VERSION 5.7 ;
  NOWIREEXTENSIONATPIN ON ;
  DIVIDERCHAR "/" ;
  BUSBITCHARS "[]" ;
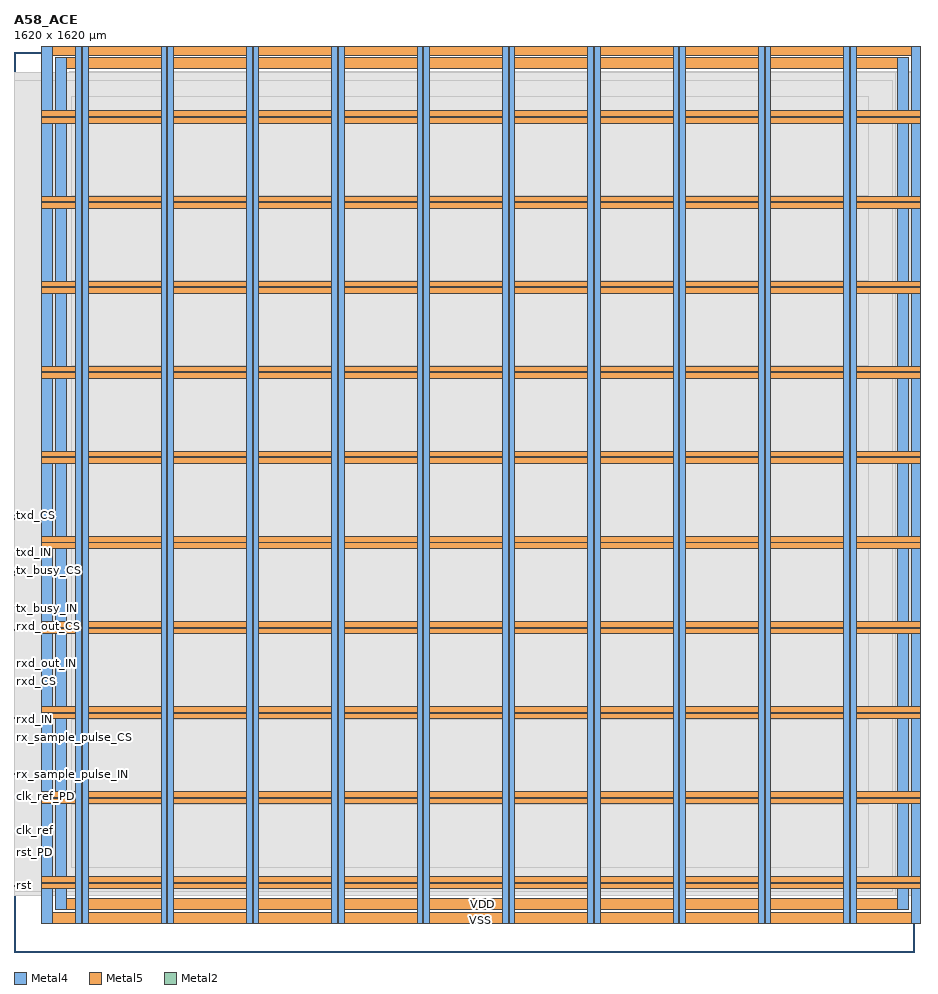
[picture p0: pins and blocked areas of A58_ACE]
MACRO A58_ACE
  CLASS BLOCK ;
  FOREIGN A58_ACE ;
  ORIGIN 0.000 0.000 ;
  SIZE 1620.000 BY 1620.000 ;
  PIN VDD
    DIRECTION INOUT ;
    USE POWER ;
    PORT
      LAYER Metal4 ;
        RECT 74.240 75.920 94.240 1609.680 ;
    END
    PORT
      LAYER Metal4 ;
        RECT 1590.800 75.920 1610.800 1609.680 ;
    END
    PORT
      LAYER Metal5 ;
        RECT 74.240 75.920 1610.800 95.920 ;
    END
    PORT
      LAYER Metal5 ;
        RECT 74.240 1589.680 1610.800 1609.680 ;
    END
    PORT
      LAYER Metal4 ;
        RECT 111.560 51.120 121.560 1634.480 ;
    END
    PORT
      LAYER Metal4 ;
        RECT 265.160 51.120 275.160 1634.480 ;
    END
    PORT
      LAYER Metal4 ;
        RECT 418.760 51.120 428.760 1634.480 ;
    END
    PORT
      LAYER Metal4 ;
        RECT 572.360 51.120 582.360 1634.480 ;
    END
    PORT
      LAYER Metal4 ;
        RECT 725.960 51.120 735.960 1634.480 ;
    END
    PORT
      LAYER Metal4 ;
        RECT 879.560 51.120 889.560 1634.480 ;
    END
    PORT
      LAYER Metal4 ;
        RECT 1033.160 51.120 1043.160 1634.480 ;
    END
    PORT
      LAYER Metal4 ;
        RECT 1186.760 51.120 1196.760 1634.480 ;
    END
    PORT
      LAYER Metal4 ;
        RECT 1340.360 51.120 1350.360 1634.480 ;
    END
    PORT
      LAYER Metal4 ;
        RECT 1493.960 51.120 1503.960 1634.480 ;
    END
    PORT
      LAYER Metal5 ;
        RECT 49.440 113.570 1635.600 123.570 ;
    END
    PORT
      LAYER Metal5 ;
        RECT 49.440 266.750 1635.600 276.750 ;
    END
    PORT
      LAYER Metal5 ;
        RECT 49.440 419.930 1635.600 429.930 ;
    END
    PORT
      LAYER Metal5 ;
        RECT 49.440 573.110 1635.600 583.110 ;
    END
    PORT
      LAYER Metal5 ;
        RECT 49.440 726.290 1635.600 736.290 ;
    END
    PORT
      LAYER Metal5 ;
        RECT 49.440 879.470 1635.600 889.470 ;
    END
    PORT
      LAYER Metal5 ;
        RECT 49.440 1032.650 1635.600 1042.650 ;
    END
    PORT
      LAYER Metal5 ;
        RECT 49.440 1185.830 1635.600 1195.830 ;
    END
    PORT
      LAYER Metal5 ;
        RECT 49.440 1339.010 1635.600 1349.010 ;
    END
    PORT
      LAYER Metal5 ;
        RECT 49.440 1492.190 1635.600 1502.190 ;
    END
  END VDD
  PIN VSS
    DIRECTION INOUT ;
    USE GROUND ;
    PORT
      LAYER Metal4 ;
        RECT 49.440 51.120 69.440 1634.480 ;
    END
    PORT
      LAYER Metal4 ;
        RECT 1615.600 51.120 1635.600 1634.480 ;
    END
    PORT
      LAYER Metal5 ;
        RECT 49.440 51.120 1635.600 71.120 ;
    END
    PORT
      LAYER Metal5 ;
        RECT 49.440 1614.480 1635.600 1634.480 ;
    END
    PORT
      LAYER Metal4 ;
        RECT 123.260 51.120 133.260 1634.480 ;
    END
    PORT
      LAYER Metal4 ;
        RECT 276.860 51.120 286.860 1634.480 ;
    END
    PORT
      LAYER Metal4 ;
        RECT 430.460 51.120 440.460 1634.480 ;
    END
    PORT
      LAYER Metal4 ;
        RECT 584.060 51.120 594.060 1634.480 ;
    END
    PORT
      LAYER Metal4 ;
        RECT 737.660 51.120 747.660 1634.480 ;
    END
    PORT
      LAYER Metal4 ;
        RECT 891.260 51.120 901.260 1634.480 ;
    END
    PORT
      LAYER Metal4 ;
        RECT 1044.860 51.120 1054.860 1634.480 ;
    END
    PORT
      LAYER Metal4 ;
        RECT 1198.460 51.120 1208.460 1634.480 ;
    END
    PORT
      LAYER Metal4 ;
        RECT 1352.060 51.120 1362.060 1634.480 ;
    END
    PORT
      LAYER Metal4 ;
        RECT 1505.660 51.120 1515.660 1634.480 ;
    END
    PORT
      LAYER Metal5 ;
        RECT 49.440 125.270 1635.600 135.270 ;
    END
    PORT
      LAYER Metal5 ;
        RECT 49.440 278.450 1635.600 288.450 ;
    END
    PORT
      LAYER Metal5 ;
        RECT 49.440 431.630 1635.600 441.630 ;
    END
    PORT
      LAYER Metal5 ;
        RECT 49.440 584.810 1635.600 594.810 ;
    END
    PORT
      LAYER Metal5 ;
        RECT 49.440 737.990 1635.600 747.990 ;
    END
    PORT
      LAYER Metal5 ;
        RECT 49.440 891.170 1635.600 901.170 ;
    END
    PORT
      LAYER Metal5 ;
        RECT 49.440 1044.350 1635.600 1054.350 ;
    END
    PORT
      LAYER Metal5 ;
        RECT 49.440 1197.530 1635.600 1207.530 ;
    END
    PORT
      LAYER Metal5 ;
        RECT 49.440 1350.710 1635.600 1360.710 ;
    END
    PORT
      LAYER Metal5 ;
        RECT 49.440 1503.890 1635.600 1513.890 ;
    END
  END VSS
  PIN clk_ref
    DIRECTION INPUT ;
    USE SIGNAL ;
    ANTENNAGATEAREA 14.368000 ;
    PORT
      LAYER Metal2 ;
        RECT 0.000 218.760 1.000 219.140 ;
    END
  END clk_ref
  PIN clk_ref_PD
    DIRECTION OUTPUT ;
    USE SIGNAL ;
    ANTENNADIFFAREA 0.360800 ;
    PORT
      LAYER Metal2 ;
        RECT 0.000 279.290 1.000 279.670 ;
    END
  END clk_ref_PD
  PIN clk_ref_PU
    DIRECTION OUTPUT ;
    USE SIGNAL ;
    ANTENNADIFFAREA 0.360800 ;
    PORT
      LAYER Metal2 ;
        RECT 0.000 283.655 1.000 284.035 ;
    END
  END clk_ref_PU
  PIN rst
    DIRECTION INPUT ;
    USE SIGNAL ;
    ANTENNAGATEAREA 4.408000 ;
    PORT
      LAYER Metal2 ;
        RECT 0.000 118.760 1.000 119.140 ;
    END
  END rst
  PIN rst_PD
    DIRECTION OUTPUT ;
    USE SIGNAL ;
    ANTENNADIFFAREA 0.360800 ;
    PORT
      LAYER Metal2 ;
        RECT 0.000 179.290 1.000 179.670 ;
    END
  END rst_PD
  PIN rst_PU
    DIRECTION OUTPUT ;
    USE SIGNAL ;
    ANTENNADIFFAREA 0.360800 ;
    PORT
      LAYER Metal2 ;
        RECT 0.000 183.655 1.000 184.035 ;
    END
  END rst_PU
  PIN rx_sample_pulse_CS
    DIRECTION OUTPUT ;
    USE SIGNAL ;
    ANTENNADIFFAREA 0.360800 ;
    PORT
      LAYER Metal2 ;
        RECT 0.000 386.260 1.000 386.640 ;
    END
  END rx_sample_pulse_CS
  PIN rx_sample_pulse_IE
    DIRECTION OUTPUT ;
    USE SIGNAL ;
    ANTENNADIFFAREA 0.360800 ;
    PORT
      LAYER Metal2 ;
        RECT 0.000 378.235 1.000 378.615 ;
    END
  END rx_sample_pulse_IE
  PIN rx_sample_pulse_IN
    DIRECTION INPUT ;
    USE SIGNAL ;
    PORT
      LAYER Metal2 ;
        RECT 0.000 318.760 1.000 319.140 ;
    END
  END rx_sample_pulse_IN
  PIN rx_sample_pulse_OE
    DIRECTION OUTPUT ;
    USE SIGNAL ;
    ANTENNADIFFAREA 0.536800 ;
    PORT
      LAYER Metal2 ;
        RECT 0.000 319.490 1.000 319.870 ;
    END
  END rx_sample_pulse_OE
  PIN rx_sample_pulse_OUT
    DIRECTION OUTPUT ;
    USE SIGNAL ;
    ANTENNADIFFAREA 1.986000 ;
    PORT
      LAYER Metal2 ;
        RECT 0.000 320.220 1.000 320.600 ;
    END
  END rx_sample_pulse_OUT
  PIN rx_sample_pulse_PD
    DIRECTION OUTPUT ;
    USE SIGNAL ;
    ANTENNADIFFAREA 0.360800 ;
    PORT
      LAYER Metal2 ;
        RECT 0.000 379.290 1.000 379.670 ;
    END
  END rx_sample_pulse_PD
  PIN rx_sample_pulse_PU
    DIRECTION OUTPUT ;
    USE SIGNAL ;
    ANTENNADIFFAREA 0.360800 ;
    PORT
      LAYER Metal2 ;
        RECT 0.000 383.655 1.000 384.035 ;
    END
  END rx_sample_pulse_PU
  PIN rx_sample_pulse_SL
    DIRECTION OUTPUT ;
    USE SIGNAL ;
    ANTENNADIFFAREA 0.360800 ;
    PORT
      LAYER Metal2 ;
        RECT 0.000 320.950 1.000 321.330 ;
    END
  END rx_sample_pulse_SL
  PIN rxd_CS
    DIRECTION OUTPUT ;
    USE SIGNAL ;
    ANTENNADIFFAREA 0.536800 ;
    PORT
      LAYER Metal2 ;
        RECT 0.000 486.260 1.000 486.640 ;
    END
  END rxd_CS
  PIN rxd_IE
    DIRECTION OUTPUT ;
    USE SIGNAL ;
    ANTENNADIFFAREA 0.536800 ;
    PORT
      LAYER Metal2 ;
        RECT 0.000 478.235 1.000 478.615 ;
    END
  END rxd_IE
  PIN rxd_IN
    DIRECTION INPUT ;
    USE SIGNAL ;
    ANTENNAGATEAREA 0.396000 ;
    PORT
      LAYER Metal2 ;
        RECT 0.000 418.760 1.000 419.140 ;
    END
  END rxd_IN
  PIN rxd_OE
    DIRECTION OUTPUT ;
    USE SIGNAL ;
    ANTENNADIFFAREA 0.360800 ;
    PORT
      LAYER Metal2 ;
        RECT 0.000 419.490 1.000 419.870 ;
    END
  END rxd_OE
  PIN rxd_PD
    DIRECTION OUTPUT ;
    USE SIGNAL ;
    ANTENNADIFFAREA 0.360800 ;
    PORT
      LAYER Metal2 ;
        RECT 0.000 479.290 1.000 479.670 ;
    END
  END rxd_PD
  PIN rxd_PU
    DIRECTION OUTPUT ;
    USE SIGNAL ;
    ANTENNADIFFAREA 0.360800 ;
    PORT
      LAYER Metal2 ;
        RECT 0.000 483.655 1.000 484.035 ;
    END
  END rxd_PU
  PIN rxd_SL
    DIRECTION OUTPUT ;
    USE SIGNAL ;
    ANTENNADIFFAREA 0.536800 ;
    PORT
      LAYER Metal2 ;
        RECT 0.000 420.950 1.000 421.330 ;
    END
  END rxd_SL
  PIN rxd_out
    DIRECTION OUTPUT ;
    USE SIGNAL ;
    ANTENNADIFFAREA 0.360800 ;
    PORT
      LAYER Metal2 ;
        RECT 0.000 420.220 1.000 420.600 ;
    END
  END rxd_out
  PIN rxd_out_CS
    DIRECTION OUTPUT ;
    USE SIGNAL ;
    ANTENNADIFFAREA 0.360800 ;
    PORT
      LAYER Metal2 ;
        RECT 0.000 586.260 1.000 586.640 ;
    END
  END rxd_out_CS
  PIN rxd_out_IE
    DIRECTION OUTPUT ;
    USE SIGNAL ;
    ANTENNADIFFAREA 0.360800 ;
    PORT
      LAYER Metal2 ;
        RECT 0.000 578.235 1.000 578.615 ;
    END
  END rxd_out_IE
  PIN rxd_out_IN
    DIRECTION INPUT ;
    USE SIGNAL ;
    PORT
      LAYER Metal2 ;
        RECT 0.000 518.760 1.000 519.140 ;
    END
  END rxd_out_IN
  PIN rxd_out_OE
    DIRECTION OUTPUT ;
    USE SIGNAL ;
    ANTENNADIFFAREA 0.536800 ;
    PORT
      LAYER Metal2 ;
        RECT 0.000 519.490 1.000 519.870 ;
    END
  END rxd_out_OE
  PIN rxd_out_OUT
    DIRECTION OUTPUT ;
    USE SIGNAL ;
    ANTENNADIFFAREA 1.986000 ;
    PORT
      LAYER Metal2 ;
        RECT 0.000 520.220 1.000 520.600 ;
    END
  END rxd_out_OUT
  PIN rxd_out_PD
    DIRECTION OUTPUT ;
    USE SIGNAL ;
    ANTENNADIFFAREA 0.360800 ;
    PORT
      LAYER Metal2 ;
        RECT 0.000 579.290 1.000 579.670 ;
    END
  END rxd_out_PD
  PIN rxd_out_PU
    DIRECTION OUTPUT ;
    USE SIGNAL ;
    ANTENNADIFFAREA 0.360800 ;
    PORT
      LAYER Metal2 ;
        RECT 0.000 583.655 1.000 584.035 ;
    END
  END rxd_out_PU
  PIN rxd_out_SL
    DIRECTION OUTPUT ;
    USE SIGNAL ;
    ANTENNADIFFAREA 0.360800 ;
    PORT
      LAYER Metal2 ;
        RECT 0.000 520.950 1.000 521.330 ;
    END
  END rxd_out_SL
  PIN tx_busy_CS
    DIRECTION OUTPUT ;
    USE SIGNAL ;
    ANTENNADIFFAREA 0.360800 ;
    PORT
      LAYER Metal2 ;
        RECT 0.000 686.260 1.000 686.640 ;
    END
  END tx_busy_CS
  PIN tx_busy_IE
    DIRECTION OUTPUT ;
    USE SIGNAL ;
    ANTENNADIFFAREA 0.360800 ;
    PORT
      LAYER Metal2 ;
        RECT 0.000 678.235 1.000 678.615 ;
    END
  END tx_busy_IE
  PIN tx_busy_IN
    DIRECTION INPUT ;
    USE SIGNAL ;
    PORT
      LAYER Metal2 ;
        RECT 0.000 618.760 1.000 619.140 ;
    END
  END tx_busy_IN
  PIN tx_busy_OE
    DIRECTION OUTPUT ;
    USE SIGNAL ;
    ANTENNADIFFAREA 0.536800 ;
    PORT
      LAYER Metal2 ;
        RECT 0.000 619.490 1.000 619.870 ;
    END
  END tx_busy_OE
  PIN tx_busy_OUT
    DIRECTION OUTPUT ;
    USE SIGNAL ;
    ANTENNADIFFAREA 1.986000 ;
    PORT
      LAYER Metal2 ;
        RECT 0.000 620.220 1.000 620.600 ;
    END
  END tx_busy_OUT
  PIN tx_busy_PD
    DIRECTION OUTPUT ;
    USE SIGNAL ;
    ANTENNADIFFAREA 0.360800 ;
    PORT
      LAYER Metal2 ;
        RECT 0.000 679.290 1.000 679.670 ;
    END
  END tx_busy_PD
  PIN tx_busy_PU
    DIRECTION OUTPUT ;
    USE SIGNAL ;
    ANTENNADIFFAREA 0.360800 ;
    PORT
      LAYER Metal2 ;
        RECT 0.000 683.655 1.000 684.035 ;
    END
  END tx_busy_PU
  PIN tx_busy_SL
    DIRECTION OUTPUT ;
    USE SIGNAL ;
    ANTENNADIFFAREA 0.360800 ;
    PORT
      LAYER Metal2 ;
        RECT 0.000 620.950 1.000 621.330 ;
    END
  END tx_busy_SL
  PIN txd_CS
    DIRECTION OUTPUT ;
    USE SIGNAL ;
    ANTENNADIFFAREA 0.360800 ;
    PORT
      LAYER Metal2 ;
        RECT 0.000 786.260 1.000 786.640 ;
    END
  END txd_CS
  PIN txd_IE
    DIRECTION OUTPUT ;
    USE SIGNAL ;
    ANTENNADIFFAREA 0.360800 ;
    PORT
      LAYER Metal2 ;
        RECT 0.000 778.235 1.000 778.615 ;
    END
  END txd_IE
  PIN txd_IN
    DIRECTION INPUT ;
    USE SIGNAL ;
    PORT
      LAYER Metal2 ;
        RECT 0.000 718.760 1.000 719.140 ;
    END
  END txd_IN
  PIN txd_OE
    DIRECTION OUTPUT ;
    USE SIGNAL ;
    ANTENNADIFFAREA 0.536800 ;
    PORT
      LAYER Metal2 ;
        RECT 0.000 719.490 1.000 719.870 ;
    END
  END txd_OE
  PIN txd_OUT
    DIRECTION OUTPUT ;
    USE SIGNAL ;
    ANTENNADIFFAREA 1.986000 ;
    PORT
      LAYER Metal2 ;
        RECT 0.000 720.220 1.000 720.600 ;
    END
  END txd_OUT
  PIN txd_PD
    DIRECTION OUTPUT ;
    USE SIGNAL ;
    ANTENNADIFFAREA 0.360800 ;
    PORT
      LAYER Metal2 ;
        RECT 0.000 779.290 1.000 779.670 ;
    END
  END txd_PD
  PIN txd_PU
    DIRECTION OUTPUT ;
    USE SIGNAL ;
    ANTENNADIFFAREA 0.360800 ;
    PORT
      LAYER Metal2 ;
        RECT 0.000 783.655 1.000 784.035 ;
    END
  END txd_PU
  PIN txd_SL
    DIRECTION OUTPUT ;
    USE SIGNAL ;
    ANTENNADIFFAREA 0.360800 ;
    PORT
      LAYER Metal2 ;
        RECT 0.000 720.950 1.000 721.330 ;
    END
  END txd_SL
  OBS
      LAYER Nwell ;
        RECT 99.810 101.490 1615.470 1584.110 ;
      LAYER Metal1 ;
        RECT 100.240 101.620 1615.040 1583.980 ;
      LAYER Metal2 ;
        RECT 0.140 786.940 1585.780 1583.870 ;
        RECT 1.300 785.960 1585.780 786.940 ;
        RECT 0.140 784.335 1585.780 785.960 ;
        RECT 1.300 783.355 1585.780 784.335 ;
        RECT 0.140 779.970 1585.780 783.355 ;
        RECT 1.300 778.990 1585.780 779.970 ;
        RECT 0.140 778.915 1585.780 778.990 ;
        RECT 1.300 777.935 1585.780 778.915 ;
        RECT 0.140 721.630 1585.780 777.935 ;
        RECT 1.300 718.460 1585.780 721.630 ;
        RECT 0.140 686.940 1585.780 718.460 ;
        RECT 1.300 685.960 1585.780 686.940 ;
        RECT 0.140 684.335 1585.780 685.960 ;
        RECT 1.300 683.355 1585.780 684.335 ;
        RECT 0.140 679.970 1585.780 683.355 ;
        RECT 1.300 678.990 1585.780 679.970 ;
        RECT 0.140 678.915 1585.780 678.990 ;
        RECT 1.300 677.935 1585.780 678.915 ;
        RECT 0.140 621.630 1585.780 677.935 ;
        RECT 1.300 618.460 1585.780 621.630 ;
        RECT 0.140 586.940 1585.780 618.460 ;
        RECT 1.300 585.960 1585.780 586.940 ;
        RECT 0.140 584.335 1585.780 585.960 ;
        RECT 1.300 583.355 1585.780 584.335 ;
        RECT 0.140 579.970 1585.780 583.355 ;
        RECT 1.300 578.990 1585.780 579.970 ;
        RECT 0.140 578.915 1585.780 578.990 ;
        RECT 1.300 577.935 1585.780 578.915 ;
        RECT 0.140 521.630 1585.780 577.935 ;
        RECT 1.300 518.460 1585.780 521.630 ;
        RECT 0.140 486.940 1585.780 518.460 ;
        RECT 1.300 485.960 1585.780 486.940 ;
        RECT 0.140 484.335 1585.780 485.960 ;
        RECT 1.300 483.355 1585.780 484.335 ;
        RECT 0.140 479.970 1585.780 483.355 ;
        RECT 1.300 478.990 1585.780 479.970 ;
        RECT 0.140 478.915 1585.780 478.990 ;
        RECT 1.300 477.935 1585.780 478.915 ;
        RECT 0.140 421.630 1585.780 477.935 ;
        RECT 1.300 418.460 1585.780 421.630 ;
        RECT 0.140 386.940 1585.780 418.460 ;
        RECT 1.300 385.960 1585.780 386.940 ;
        RECT 0.140 384.335 1585.780 385.960 ;
        RECT 1.300 383.355 1585.780 384.335 ;
        RECT 0.140 379.970 1585.780 383.355 ;
        RECT 1.300 378.990 1585.780 379.970 ;
        RECT 0.140 378.915 1585.780 378.990 ;
        RECT 1.300 377.935 1585.780 378.915 ;
        RECT 0.140 321.630 1585.780 377.935 ;
        RECT 1.300 318.460 1585.780 321.630 ;
        RECT 0.140 284.335 1585.780 318.460 ;
        RECT 1.300 283.355 1585.780 284.335 ;
        RECT 0.140 279.970 1585.780 283.355 ;
        RECT 1.300 278.990 1585.780 279.970 ;
        RECT 0.140 219.440 1585.780 278.990 ;
        RECT 1.300 218.460 1585.780 219.440 ;
        RECT 0.140 184.335 1585.780 218.460 ;
        RECT 1.300 183.355 1585.780 184.335 ;
        RECT 0.140 179.970 1585.780 183.355 ;
        RECT 1.300 178.990 1585.780 179.970 ;
        RECT 0.140 119.440 1585.780 178.990 ;
        RECT 1.300 118.460 1585.780 119.440 ;
        RECT 0.140 101.730 1585.780 118.460 ;
      LAYER Metal3 ;
        RECT 0.090 101.780 1585.830 1583.820 ;
      LAYER Metal4 ;
        RECT 0.140 108.730 49.140 1569.590 ;
        RECT 69.740 108.730 73.940 1569.590 ;
        RECT 94.540 108.730 111.260 1569.590 ;
        RECT 121.860 108.730 122.960 1569.590 ;
        RECT 133.560 108.730 264.860 1569.590 ;
        RECT 275.460 108.730 276.560 1569.590 ;
        RECT 287.160 108.730 418.460 1569.590 ;
        RECT 429.060 108.730 430.160 1569.590 ;
        RECT 440.760 108.730 572.060 1569.590 ;
        RECT 582.660 108.730 583.760 1569.590 ;
        RECT 594.360 108.730 725.660 1569.590 ;
        RECT 736.260 108.730 737.360 1569.590 ;
        RECT 747.960 108.730 879.260 1569.590 ;
        RECT 889.860 108.730 890.960 1569.590 ;
        RECT 901.560 108.730 1032.860 1569.590 ;
        RECT 1043.460 108.730 1044.560 1569.590 ;
        RECT 1055.160 108.730 1186.460 1569.590 ;
        RECT 1197.060 108.730 1198.160 1569.590 ;
        RECT 1208.760 108.730 1340.060 1569.590 ;
        RECT 1350.660 108.730 1351.760 1569.590 ;
        RECT 1362.360 108.730 1493.660 1569.590 ;
        RECT 1504.260 108.730 1505.360 1569.590 ;
        RECT 1515.960 108.730 1580.740 1569.590 ;
      LAYER Metal5 ;
        RECT 103.660 1514.490 1538.260 1539.670 ;
        RECT 103.660 1502.790 1538.260 1503.290 ;
        RECT 103.660 1361.310 1538.260 1491.590 ;
        RECT 103.660 1349.610 1538.260 1350.110 ;
        RECT 103.660 1208.130 1538.260 1338.410 ;
        RECT 103.660 1196.430 1538.260 1196.930 ;
        RECT 103.660 1054.950 1538.260 1185.230 ;
        RECT 103.660 1043.250 1538.260 1043.750 ;
        RECT 103.660 901.770 1538.260 1032.050 ;
        RECT 103.660 890.070 1538.260 890.570 ;
        RECT 103.660 748.590 1538.260 878.870 ;
        RECT 103.660 736.890 1538.260 737.390 ;
        RECT 103.660 595.410 1538.260 725.690 ;
        RECT 103.660 583.710 1538.260 584.210 ;
        RECT 103.660 442.230 1538.260 572.510 ;
        RECT 103.660 430.530 1538.260 431.030 ;
        RECT 103.660 289.050 1538.260 419.330 ;
        RECT 103.660 277.350 1538.260 277.850 ;
        RECT 103.660 151.430 1538.260 266.150 ;
  END
END A58_ACE
END LIBRARY

